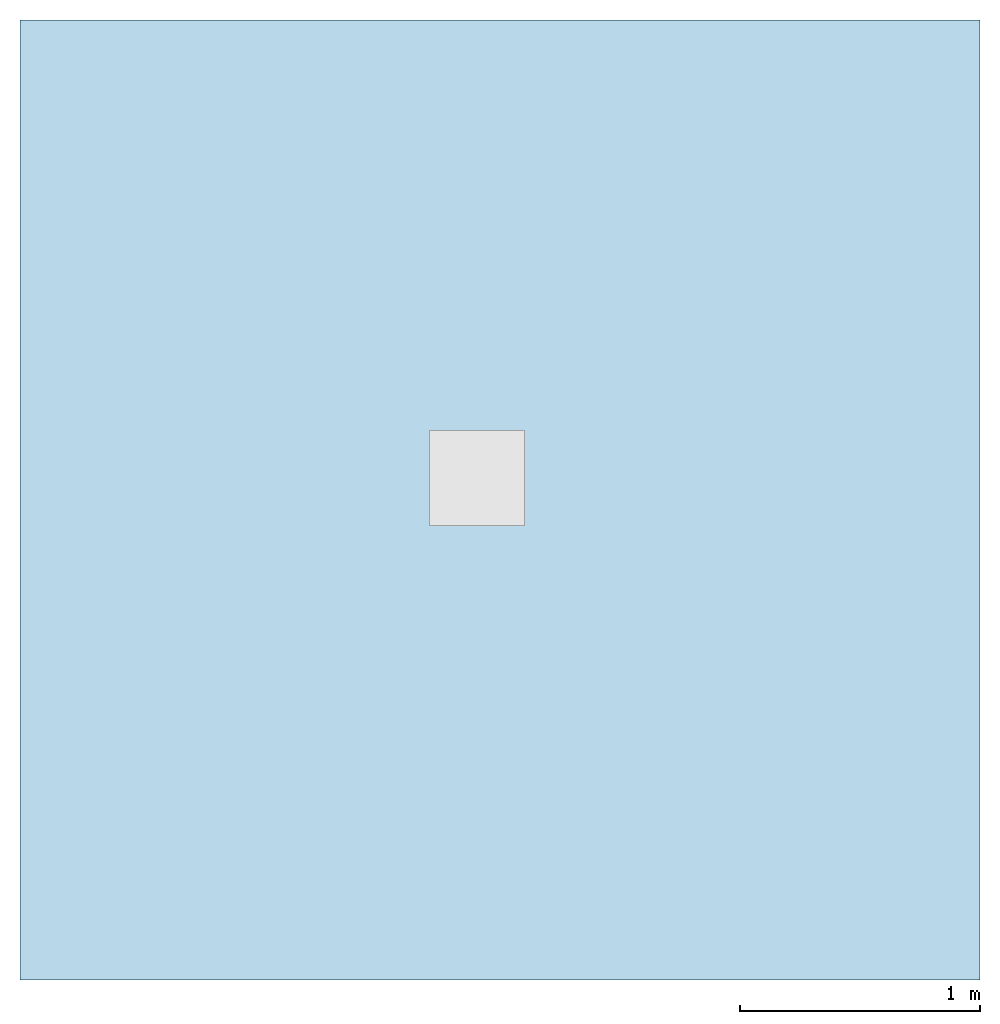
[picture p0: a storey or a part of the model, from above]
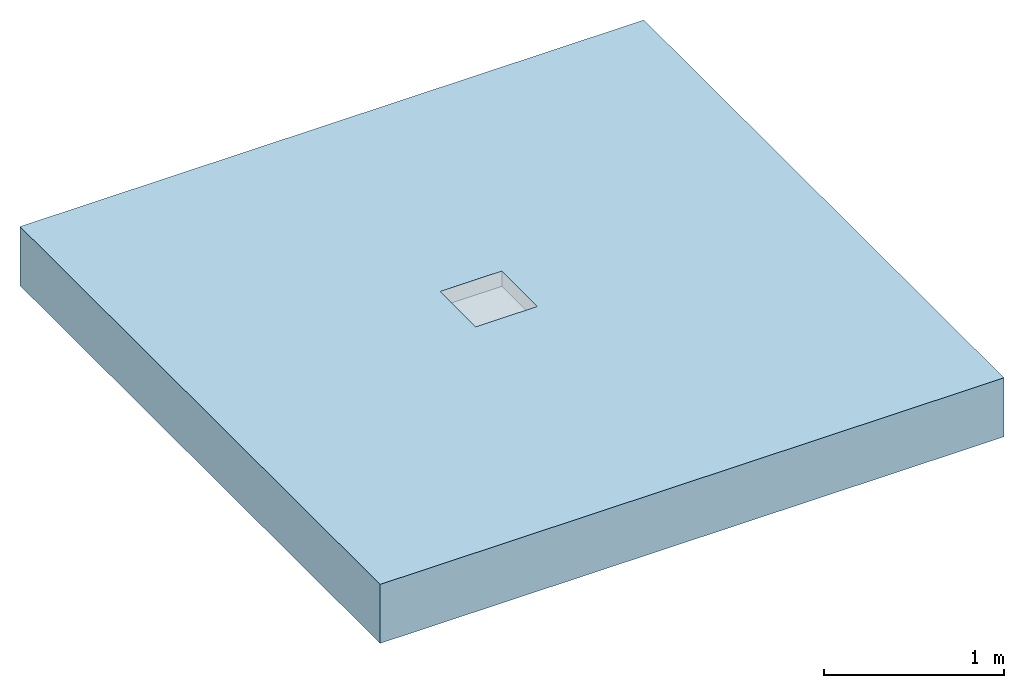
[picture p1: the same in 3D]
Properties of the parts of a building model (IFC2X3)

# File
Description: ViewDefinition [CoordinationView]
File name: Project Number
Time: 2014-06-06T10:57:50
Written by: The EXPRESS Data Manager Version 5.01.0100.02.64mod : 6 Jun 2012
Made in: 20130308_1515(x64) - Exporter 2014.0.2013.0308 - Default UI
Comment: STEP Physical File produced by: The EXPRESS Data Manager Version 5.01.0100.02.64mod : 6 Jun 2012 * Module: EDMstepFileFactory/EDMstandAlone * Creation date: Fri Jun 06 10:57:50 2014 * Host: IN-BLR-PC-0010 * Database: C:\Users\palleri\AppData\Local\Temp\{DA98D343-2EBC-455E-ACA5-B7B163137075}\ifc * Database version: 5507 * Database creation date: Fri Jun 06 10:57:49 2014 * Schema: IFC2X3 * Model: DataRepository.ifc * Model creation date: Fri Jun 06 10:57:49 2014 * Header model: DataRepository.ifc_HeaderModel * Header model creation date: Fri Jun 06 10:57:49 2014 * EDMuser: sdai-user * EDMgroup: sdai-group * License ID and type: 5605 : Permanent license. Expiry date: * EDMstepFileFactory options: 020000

# IfcProject, Project Number
LongName: Project Name; Phase: Project Status

# IfcSite, Default
RefLatitude: 42, 21, 30, 344238; RefLongitude: -71, -3, -35, -194702; RefElevation: 0 mm

# IfcBuilding
Pset_BuildingCommon - NumberOfStoreys: 1
Other - Project Issue Date: Issue Date; Project Name: Project Name; Client Name: Owner; Project Number: Project Number; Project Address: ## Street City, State Zip; Project Status: Project Status

# IfcBuildingStorey, Level 1
LongName: Level 1; Elevation: 0 mm
Constraints - Elevation Base: Project Base Point; Elevation: 0 mm
Graphics - Symbol: M_Level Head - Circle: M_Level Head - Circle; Line Pattern: Center; Symbol at End 1 Default: no; Symbol at End 2 Default: yes; Line Weight: 1; Color: 0
Identity Data - Building Story: yes; Name: Level 1; Structural: no
Dimensions - Computation Height: 0 mm

# IfcFlowTerminal: 38150 - Access Frame - Fixed Height - Invert Depth 50mm, ACO Freedeck Access Frame & Drain Duct (Accessories part 1) V1.27 - GS:38150 - Access Frame - Fixed Height - Invert Depth 50mm:276243
In: Level 1
Material: Galvanized Steel
Materials and Finishes - Material: Galvanized Steel
Dimensions - Top Void Height End: -55 mm; Base Height: 3000 mm; Height for Adjustable Access Frame: 105 mm; Drainage Duct – Level below FFL: 30 mm; Total Height: 159 mm; Top Void Height Start: -105 mm; Access Frame Extension Position Height: 0 mm; Grating End: -20 mm; Grating Start: 0 mm; Drain Duct End: -100 mm
Other - Access Frame Extension Height: 75 mm; Access Frame Extension_Invert Depth 75mm: yes; Adjustable Access Frame Position Height: 105 mm; Fixed Access Frame Position Height: 105 mm; Access Frame Extension_Invert Depth 50mm: no; Extension Removal Void: -2 mm; Access Frame Extension: yes; Drain Duct Vertical Height: 5000 mm; Access Frame Adjustable Height: no; Drain Duct: no; Access Frame Fixed Height: yes; Top void Size: 400 mm; Grating: yes
Constraints - Level: Level: Level 1; Moves With Nearby Elements: no
Phasing - Phase Created: New Construction
Identity Data - Mark: 14; Watermark1: This file is the property of ACO Technologies PLC; Fax: +44 (0)1462 851490; Website: www.acobd.com; Telephone: +44 (0)1462 816666; Address: ACO Business Centre, Caxton Road, Bedford, MK41 0LF; E-mail Sales: abdcommercial@aco.co.uk; E-mail Technical: abdtechnical@aco.co.uk; Watermarked With: BIM Manager Premium Suite; Watermark2: This file is water marked and users are prohibited to reproduce, adapt, distribute this information; Manufacturer: ACO Building Drainage; Watermarked By: www.acobd.com
Construction - 38685_Access Frame Extension_Galvanized Steel_Invert Depth 50mm: no; 38687_Access Frame Extension_Galvanized Steel_Invert Depth 75mm: yes; 36754_Access Grating_Mesh Grating_Galvanized Steel: yes
Pset_ManufacturerTypeInformation - Manufacturer: ACO Building Drainage
Model Properties - Access Frame Extension Product Code 38686: N/A; Access Frame Extension Product Code 38688: N/A; Access Frame Extension Product Code 38687: Load Class A15 - Access Frame Extension - Galvanized Steel - Invert Depth 75mm - 1.9kg; Access Frame Extension Product Code 38685: Load Class A15 - Access Frame Extension - Galvanized Steel - Invert Depth 50mm - 1.3kg; Access Grating Product Code 36760: N/A; Access Grating Product Code 36754: Load Class A15 - Mesh Grating - 14mm x 30mm Mesh - Galvanized Steel - 3.5kg
General - Maintenance Guidelines: X:\Electronic Literature\ABD Electronic Literature\Roof and Balcony Drainage\ACO Freedeck Brochure.pdf; Product Code: 38150; Price: POA - contact ACO; Channel Recycled Material Content: 25 - 30 %; Product Description: ACO Freedeck Access Frame - Adjustable; Dimensions (LxWxH): 400 x 400 x 50; Weight (Kg): 5.7kg; Product Type: Linear Deck Drainage System; Channel Recyclable: Fully recyclable; Product Range: ACO Freedeck; Product Standard: BS EN 1433:2002, CE marked; Channel Material: Hot Dipped Galvanised Steel; Installation Guidelines: X:\Electronic Literature\ABD Electronic Literature\Roof and Balcony Drainage\ACO Freedeck Brochure.pdf; Channel Colour: Galvanised; Load Class: A15; NBS Specification: NBS Section R10 Gravity Rainwater Drainage Systems, Subsection 365

# IfcOpeningElement: Opening (3)
In: Level 1
Phasing - Phase Created: New Construction
Dimensions - Perimeter: 16000 mm; Area: 16 m2; Volume: 6.38342 m3; Thickness: 400 mm
Structural - Enable Analytical Model: no; Structural: no
Constraints - Level: Level: Level 1; Related to Mass: no; Room Bounding: yes; Height Offset From Level: 0 mm
Analytical Properties - Thermal Resistance (R): 0.382409; Thermal mass: 604440; Roughness: 1; Heat Transfer Coefficient (U): 2.615; Absorptance: 0.1
Construction - Function: Interior; Default Thickness: 400 mm
Graphics - Coarse Scale Fill Color: 0
Materials and Finishes - Structural Material: Concrete, Broom Finish

# IfcSlab: Floor:Generic Floor - 400mm, Floor:Generic Floor - 400mm:193825
In: Level 1
PredefinedType: FLOOR; Material: Concrete, Broom Finish 400 mm
Phasing - Phase Created: New Construction
Dimensions - Perimeter: 16000 mm; Area: 16 m2; Volume: 6.38342 m3; Thickness: 400 mm
Structural - Enable Analytical Model: no; Structural: no
Constraints - Level: Level: Level 1; Related to Mass: no; Room Bounding: yes; Height Offset From Level: 0 mm
Pset_SlabCommon - Reference: Generic Floor - 400mm; IsExternal: no; LoadBearing: yes; ThermalTransmittance: 2.615 kg/K/s3
Analytical Properties - Thermal Resistance (R): 0.382409; Thermal mass: 604440; Roughness: 1; Heat Transfer Coefficient (U): 2.615; Absorptance: 0.1
Construction - Function: Interior; Default Thickness: 400 mm
Graphics - Coarse Scale Fill Color: 0
Materials and Finishes - Structural Material: Concrete, Broom Finish
